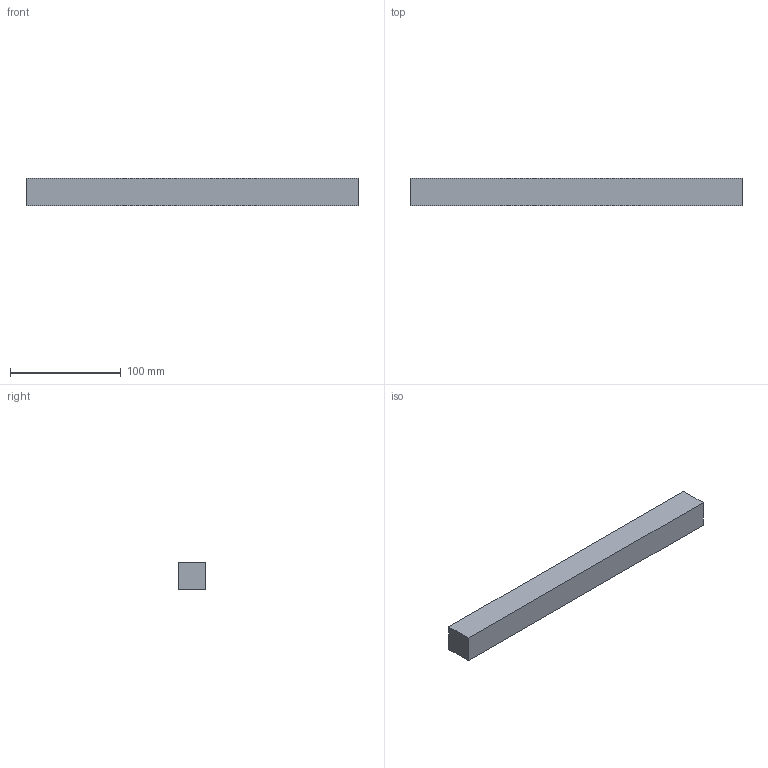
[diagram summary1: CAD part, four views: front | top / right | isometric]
IGES file: header records copied from the file, then geometry measured from it (millimetres).
Start section: START RECORD GO HERE.
Global section: file name: G40525300.igs; native system: DASSAULT SYSTEMES CATIA V5 R20 - www.3ds.com; preprocessor: CATIA Version 5 Release 20 ; author: r.borello; organization: CFTORINO; date: 20190624.150007; units: millimetre
Bounding box: 300 x 25 x 25 mm (x, y, z)
Surface area: 39602.8 mm2 (no closed solid volume)
Topology: 0 solids, 0 shells, 942 faces, 4014 edges, 3568 vertices
Faces by surface type: revolution 838, plane 104
